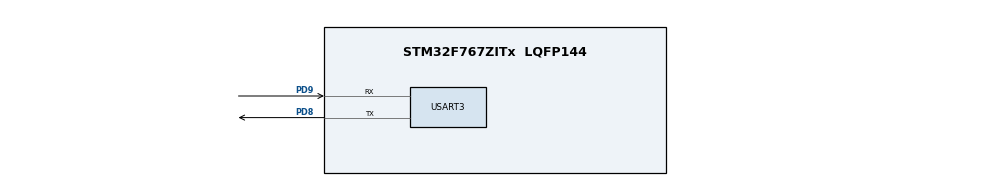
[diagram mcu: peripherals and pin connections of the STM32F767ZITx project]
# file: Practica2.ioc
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CORTEX_M7.default_mode_Activation=1
Mcu.Family=STM32F7
Mcu.Name=STM32F767ZITx
Mcu.Package=LQFP144
NVIC.PriorityGroup=NVIC_PRIORITYGROUP_4
NVIC.USART3_IRQn=true\:0\:0\:false\:false\:true\:true\:true\:true
PD8.Mode=Asynchronous
PD8.Signal=USART3_TX
PD9.Mode=Asynchronous
PD9.Signal=USART3_RX
ProjectManager.HeapSize=0x200
ProjectManager.StackSize=0x400
ProjectManager.TargetToolchain=STM32CubeIDE
RCC.HSE_VALUE=25000000
RCC.HSI_VALUE=16000000
RCC.LSE_VALUE=32768
RCC.USBFreq_Value=96000000
RCC.VCOOutputFreq_Value=192000000
USART3.VirtualMode-Asynchronous=VM_ASYNC
board=custom

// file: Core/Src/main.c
/* USER CODE BEGIN Header */

/**

  ******************************************************************************

  * @file           : main.c

  * @brief          : Main program body

  ******************************************************************************

  * @attention

  *

  * Copyright (c) 2025 STMicroelectronics.

  * All rights reserved.

  *

  * This software is licensed under terms that can be found in the LICENSE file

  * in the root directory of this software component.

  * If no LICENSE file comes with this software, it is provided AS-IS.

  *

  ******************************************************************************

  */

/* USER CODE END Header */

#include "main.h"

#include "string.h"

#if defined ( __ICCARM__ ) /*!< IAR Compiler */

#pragma location=0x2007c000

ETH_DMADescTypeDef  DMARxDscrTab[ETH_RX_DESC_CNT]; /* Ethernet Rx DMA Descriptors */

#pragma location=0x2007c0a0

ETH_DMADescTypeDef  DMATxDscrTab[ETH_TX_DESC_CNT]; /* Ethernet Tx DMA Descriptors */

#elif defined ( __CC_ARM )  /* MDK ARM Compiler */

__attribute__((at(0x2007c000))) ETH_DMADescTypeDef  DMARxDscrTab[ETH_RX_DESC_CNT]; /* Ethernet Rx DMA Descriptors */

__attribute__((at(0x2007c0a0))) ETH_DMADescTypeDef  DMATxDscrTab[ETH_TX_DESC_CNT]; /* Ethernet Tx DMA Descriptors */

#elif defined ( __GNUC__ ) /* GNU Compiler */

ETH_DMADescTypeDef DMARxDscrTab[ETH_RX_DESC_CNT] __attribute__((section(".RxDecripSection"))); /* Ethernet Rx DMA Descriptors */

ETH_DMADescTypeDef DMATxDscrTab[ETH_TX_DESC_CNT] __attribute__((section(".TxDecripSection")));   /* Ethernet Tx DMA Descriptors */

#endif

ETH_TxPacketConfig TxConfig;

ETH_HandleTypeDef heth;

UART_HandleTypeDef huart3;

PCD_HandleTypeDef hpcd_USB_OTG_FS;

void SystemClock_Config(void);

static void MX_GPIO_Init(void);

static void MX_ETH_Init(void);

static void MX_USART3_UART_Init(void);

static void MX_USB_OTG_FS_PCD_Init(void);

/* USER CODE BEGIN 0 */

uint8_t rx_buffer[16];

int led_number;

char status[3];

/* USER CODE END 0 */

int main(void)

{

  /* MCU Configuration--------------------------------------------------------*/

  /* Reset of all peripherals, Initializes the Flash interface and the Systick. */

  HAL_Init();

  /* Configure the system clock */

  SystemClock_Config();

  /* Initialize all configured peripherals */

  MX_GPIO_Init();

  MX_ETH_Init();

  MX_USART3_UART_Init();

  MX_USB_OTG_FS_PCD_Init();

  /* USER CODE BEGIN 2 */

  HAL_UART_Receive_IT(&huart3, rx_buffer, sizeof(rx_buffer));

  /* USER CODE END 2 */

  /* Infinite loop */

  /* USER CODE BEGIN WHILE */

  while (1)

  {

	  switch(led_number)

	  {

	  case 1:

		  if((status[0] == 'O') && (status[1] == 'N') && (status[2] == 'X'))

		  {

			  HAL_GPIO_WritePin(GPIOB, GPIO_PIN_0, GPIO_PIN_SET);

		  }

		  if((status[0] == 'O') && (status[1] == 'F') && (status[2] == 'F'))

		  {

			  HAL_GPIO_WritePin(GPIOB, GPIO_PIN_0, GPIO_PIN_RESET);

		  }

		  break;

	  case 2:

		  if((status[0] == 'O') && (status[1] == 'N') && (status[2] == 'X'))

		  {

			  HAL_GPIO_WritePin(GPIOB, GPIO_PIN_7, GPIO_PIN_SET);

		  }

		  if((status[0] == 'O') && (status[1] == 'F') && (status[2] == 'F'))

		  {

			  HAL_GPIO_WritePin(GPIOB, GPIO_PIN_7, GPIO_PIN_RESET);

		  }

		  break;

	  case 3:

		  if((status[0] == 'O') && (status[1] == 'N') && (status[2] == 'X'))

		  {

			  HAL_GPIO_WritePin(GPIOB, GPIO_PIN_14, GPIO_PIN_SET);

		  }

		  if((status[0] == 'O') && (status[1] == 'F') && (status[2] == 'F'))

		  {

			  HAL_GPIO_WritePin(GPIOB, GPIO_PIN_14, GPIO_PIN_RESET);

		  }

		  break;

	  }

    /* USER CODE END WHILE */

  }

}

void SystemClock_Config(void)

{

  RCC_OscInitTypeDef RCC_OscInitStruct = {0};

  RCC_ClkInitTypeDef RCC_ClkInitStruct = {0};

  /** Configure LSE Drive Capability

  */

  HAL_PWR_EnableBkUpAccess();

  /** Configure the main internal regulator output voltage

  */

  __HAL_RCC_PWR_CLK_ENABLE();

  __HAL_PWR_VOLTAGESCALING_CONFIG(PWR_REGULATOR_VOLTAGE_SCALE3);

  /** Initializes the RCC Oscillators according to the specified parameters

  * in the RCC_OscInitTypeDef structure.

  */

  RCC_OscInitStruct.OscillatorType = RCC_OSCILLATORTYPE_HSE;

  RCC_OscInitStruct.HSEState = RCC_HSE_BYPASS;

  RCC_OscInitStruct.PLL.PLLState = RCC_PLL_ON;

  RCC_OscInitStruct.PLL.PLLSource = RCC_PLLSOURCE_HSE;

  RCC_OscInitStruct.PLL.PLLM = 4;

  RCC_OscInitStruct.PLL.PLLN = 96;

  RCC_OscInitStruct.PLL.PLLP = RCC_PLLP_DIV2;

  RCC_OscInitStruct.PLL.PLLQ = 4;

  RCC_OscInitStruct.PLL.PLLR = 2;

  if (HAL_RCC_OscConfig(&RCC_OscInitStruct) != HAL_OK)

  {

    Error_Handler();

  }

  /** Activate the Over-Drive mode

  */

  if (HAL_PWREx_EnableOverDrive() != HAL_OK)

  {

    Error_Handler();

  }

  /** Initializes the CPU, AHB and APB buses clocks

  */

  RCC_ClkInitStruct.ClockType = RCC_CLOCKTYPE_HCLK|RCC_CLOCKTYPE_SYSCLK

                              |RCC_CLOCKTYPE_PCLK1|RCC_CLOCKTYPE_PCLK2;

  RCC_ClkInitStruct.SYSCLKSource = RCC_SYSCLKSOURCE_PLLCLK;

  RCC_ClkInitStruct.AHBCLKDivider = RCC_SYSCLK_DIV1;

  RCC_ClkInitStruct.APB1CLKDivider = RCC_HCLK_DIV2;

  RCC_ClkInitStruct.APB2CLKDivider = RCC_HCLK_DIV1;

  if (HAL_RCC_ClockConfig(&RCC_ClkInitStruct, FLASH_LATENCY_3) != HAL_OK)

  {

    Error_Handler();

  }

}

static void MX_ETH_Init(void)

{

   static uint8_t MACAddr[6];

  heth.Instance = ETH;

  MACAddr[0] = 0x00;

  MACAddr[1] = 0x80;

  MACAddr[2] = 0xE1;

  MACAddr[3] = 0x00;

  MACAddr[4] = 0x00;

  MACAddr[5] = 0x00;

  heth.Init.MACAddr = &MACAddr[0];

  heth.Init.MediaInterface = HAL_ETH_RMII_MODE;

  heth.Init.TxDesc = DMATxDscrTab;

  heth.Init.RxDesc = DMARxDscrTab;

  heth.Init.RxBuffLen = 1524;

  if (HAL_ETH_Init(&heth) != HAL_OK)

  {

    Error_Handler();

  }

  memset(&TxConfig, 0 , sizeof(ETH_TxPacketConfig));

  TxConfig.Attributes = ETH_TX_PACKETS_FEATURES_CSUM | ETH_TX_PACKETS_FEATURES_CRCPAD;

  TxConfig.ChecksumCtrl = ETH_CHECKSUM_IPHDR_PAYLOAD_INSERT_PHDR_CALC;

  TxConfig.CRCPadCtrl = ETH_CRC_PAD_INSERT;

}

static void MX_USART3_UART_Init(void)

{

  huart3.Instance = USART3;

  huart3.Init.BaudRate = 115200;

  huart3.Init.WordLength = UART_WORDLENGTH_8B;

  huart3.Init.StopBits = UART_STOPBITS_1;

  huart3.Init.Parity = UART_PARITY_NONE;

  huart3.Init.Mode = UART_MODE_TX_RX;

  huart3.Init.HwFlowCtl = UART_HWCONTROL_NONE;

  huart3.Init.OverSampling = UART_OVERSAMPLING_16;

  huart3.Init.OneBitSampling = UART_ONE_BIT_SAMPLE_DISABLE;

  huart3.AdvancedInit.AdvFeatureInit = UART_ADVFEATURE_NO_INIT;

  if (HAL_UART_Init(&huart3) != HAL_OK)

  {

    Error_Handler();

  }

}

static void MX_USB_OTG_FS_PCD_Init(void)

{

  hpcd_USB_OTG_FS.Instance = USB_OTG_FS;

  hpcd_USB_OTG_FS.Init.dev_endpoints = 6;

  hpcd_USB_OTG_FS.Init.speed = PCD_SPEED_FULL;

  hpcd_USB_OTG_FS.Init.dma_enable = DISABLE;

  hpcd_USB_OTG_FS.Init.phy_itface = PCD_PHY_EMBEDDED;

  hpcd_USB_OTG_FS.Init.Sof_enable = ENABLE;

  hpcd_USB_OTG_FS.Init.low_power_enable = DISABLE;

  hpcd_USB_OTG_FS.Init.lpm_enable = DISABLE;

  hpcd_USB_OTG_FS.Init.vbus_sensing_enable = ENABLE;

  hpcd_USB_OTG_FS.Init.use_dedicated_ep1 = DISABLE;

  if (HAL_PCD_Init(&hpcd_USB_OTG_FS) != HAL_OK)

  {

    Error_Handler();

  }

}

static void MX_GPIO_Init(void)

{

  GPIO_InitTypeDef GPIO_InitStruct = {0};

  /* GPIO Ports Clock Enable */

  __HAL_RCC_GPIOC_CLK_ENABLE();

  __HAL_RCC_GPIOH_CLK_ENABLE();

  __HAL_RCC_GPIOA_CLK_ENABLE();

  __HAL_RCC_GPIOB_CLK_ENABLE();

  __HAL_RCC_GPIOD_CLK_ENABLE();

  __HAL_RCC_GPIOG_CLK_ENABLE();

  /*Configure GPIO pin Output Level */

  HAL_GPIO_WritePin(GPIOB, LD1_Pin|LD3_Pin|LD2_Pin, GPIO_PIN_RESET);

  /*Configure GPIO pin Output Level */

  HAL_GPIO_WritePin(USB_PowerSwitchOn_GPIO_Port, USB_PowerSwitchOn_Pin, GPIO_PIN_RESET);

  /*Configure GPIO pin : USER_Btn_Pin */

  GPIO_InitStruct.Pin = USER_Btn_Pin;

  GPIO_InitStruct.Mode = GPIO_MODE_IT_RISING;

  GPIO_InitStruct.Pull = GPIO_NOPULL;

  HAL_GPIO_Init(USER_Btn_GPIO_Port, &GPIO_InitStruct);

  /*Configure GPIO pins : LD1_Pin LD3_Pin LD2_Pin */

  GPIO_InitStruct.Pin = LD1_Pin|LD3_Pin|LD2_Pin;

  GPIO_InitStruct.Mode = GPIO_MODE_OUTPUT_PP;

  GPIO_InitStruct.Pull = GPIO_NOPULL;

  GPIO_InitStruct.Speed = GPIO_SPEED_FREQ_LOW;

  HAL_GPIO_Init(GPIOB, &GPIO_InitStruct);

  /*Configure GPIO pin : USB_PowerSwitchOn_Pin */

  GPIO_InitStruct.Pin = USB_PowerSwitchOn_Pin;

  GPIO_InitStruct.Mode = GPIO_MODE_OUTPUT_PP;

  GPIO_InitStruct.Pull = GPIO_NOPULL;

  GPIO_InitStruct.Speed = GPIO_SPEED_FREQ_LOW;

  HAL_GPIO_Init(USB_PowerSwitchOn_GPIO_Port, &GPIO_InitStruct);

  /*Configure GPIO pin : USB_OverCurrent_Pin */

  GPIO_InitStruct.Pin = USB_OverCurrent_Pin;

  GPIO_InitStruct.Mode = GPIO_MODE_INPUT;

  GPIO_InitStruct.Pull = GPIO_NOPULL;

  HAL_GPIO_Init(USB_OverCurrent_GPIO_Port, &GPIO_InitStruct);

}

/* USER CODE BEGIN 4 */

  void HAL_UART_RxCpltCallback(UART_HandleTypeDef *
